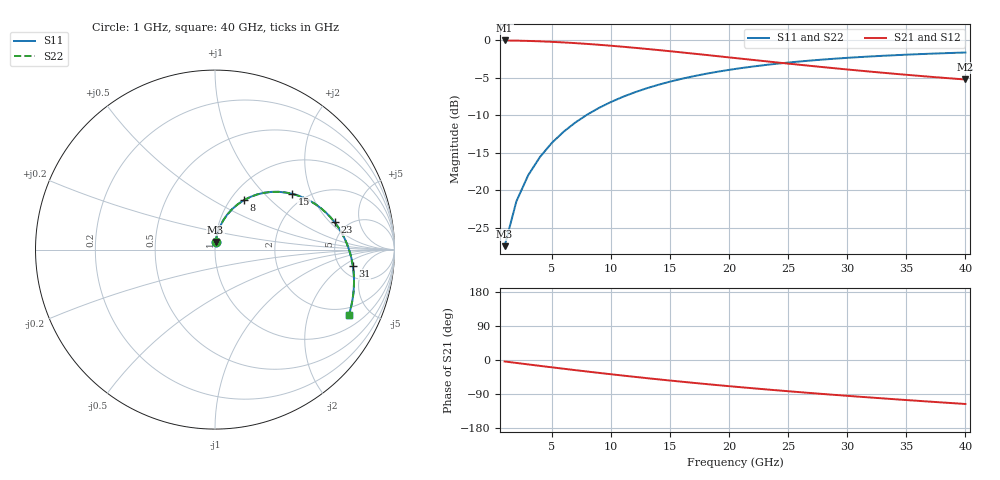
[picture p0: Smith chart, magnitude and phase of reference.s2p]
! circuitRF F0 spike reference -- case A, Palace, round wire as PEC (lossless twin, for openEMS)
! Palace postpro/port-S.csv, dB/deg -> RI; port 1 excited only; S22 = S11 and S12 = S21 by the mirror symmetry of the geometry about x = 0
# GHz S RI R 50
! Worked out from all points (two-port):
!   40 points, 1 GHz to 40 GHz, reference 50 ohm
!   highest |S21| = -0.01 dB at 1 GHz (marker M1); lowest = -5.2 dB at 40 GHz (marker M2)
!   |S21| within 3 dB of the highest: start of sweep to 24.47 GHz
!   lowest |S11| = -27.5 dB at 1 GHz (marker M3), VSWR 1.09, Z = 50.1 + j4.25 ohm
!   |S11| at or under -10 dB: start of sweep to 7.899 GHz
!   |S22| runs from -27.5 to -1.6 dB; largest |S21 - S12| = 0
!   S11 on the Smith chart (normalised r, x): 1 GHz: 1.00, +0.08; 8 GHz: 1.15, +0.71; 15 GHz: 1.71, +1.48; 23 GHz: 3.98, +2.27; 31 GHz: 6.47, -2.94; 40 GHz: 1.58, -3.69
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1  0.00288 0.0423  0.9968 -0.068  0.9968 -0.068  0.00288 0.0423
2  0.0115 0.0837  0.9872 -0.1351  0.9872 -0.1351  0.0115 0.0837
3  0.0255 0.1236  0.9715 -0.2006  0.9715 -0.2006  0.0255 0.1236
4  0.0447 0.1611  0.95 -0.2637  0.95 -0.2637  0.0447 0.1611
5  0.0685 0.1955  0.9232 -0.3236  0.9232 -0.3236  0.0685 0.1955
6  0.0964 0.2264  0.8916 -0.38  0.8916 -0.38  0.0964 0.2264
7  0.1279 0.2534  0.8558 -0.4323  0.8558 -0.4323  0.1279 0.2534
8  0.1621 0.276  0.8165 -0.4801  0.8165 -0.4801  0.1621 0.276
9  0.1986 0.2942  0.7744 -0.5234  0.7744 -0.5234  0.1986 0.2942
11  0.2756 0.3168  0.6842 -0.5958  0.6842 -0.5958  0.2756 0.3168
12  0.3149 0.3215  0.6373 -0.625  0.6373 -0.625  0.3149 0.3215
14  0.3927 0.3182  0.5425 -0.6703  0.5425 -0.6703  0.3927 0.3182
15  0.4302 0.3108  0.4954 -0.6868  0.4954 -0.6868  0.4302 0.3108
18  0.534 0.2689  0.3594 -0.7152  0.3594 -0.7152  0.534 0.2689
21  0.6205 0.204  0.2354 -0.718  0.2354 -0.718  0.6205 0.204
23  0.6672 0.1517  0.1606 -0.7092  0.1606 -0.7092  0.6672 0.1517
25  0.705 0.0946  0.0925 -0.6941  0.0925 -0.6941  0.705 0.0946
27  0.7342 0.0342  0.0308 -0.6742  0.0308 -0.6742  0.7342 0.0342
31  0.7682 -0.0911  -0.0745 -0.6246  -0.0745 -0.6246  0.7682 -0.0911
34  0.7745 -0.1852  -0.1396 -0.5824  -0.1396 -0.5824  0.7745 -0.1852
37  0.7665 -0.2768  -0.1946 -0.538  -0.1946 -0.538  0.7665 -0.2768
40  0.7459 -0.3643  -0.2409 -0.4928  -0.2409 -0.4928  0.7459 -0.3643
